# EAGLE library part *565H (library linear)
PLL

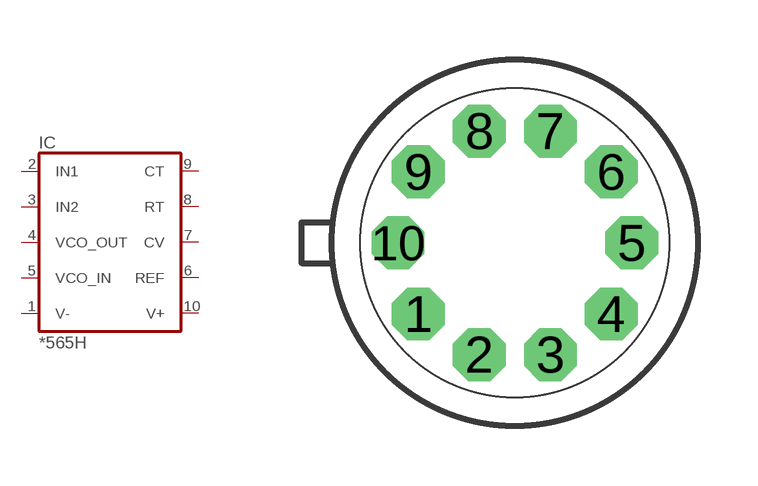
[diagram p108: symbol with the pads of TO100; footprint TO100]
Designator prefix IC

## LM565H  [TO100]
1  V-  pwr
2  IN1  in
3  IN2  in
4  VCO_OUT  out
5  VCO_IN  in
6  REF  out
7  CV  in
8  RT  pas
9  CT  pas
10  V+  pwr

## Footprint TO100 (pad centres in mm)
Metal Can Package
drill 0.813 octagon: 1 -2.413,-1.778; 2 -0.889,-2.794; 3 0.889,-2.794; 4 2.413,-1.778; 5 2.921,0; 6 2.413,1.778; 7 0.889,2.794; 8 -0.889,2.794; 9 -2.413,1.778; 10 -2.921,0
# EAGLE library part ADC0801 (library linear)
8-bit A/D CONVERTER

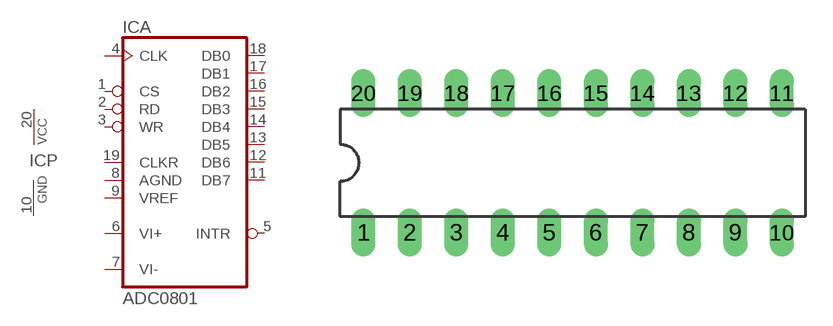
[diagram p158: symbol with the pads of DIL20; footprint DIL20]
Designator prefix IC; gates A=ADC0801 P=PWRN

## ADC0801  [DIL20]
1  A:CS  in
2  A:RD  in
3  A:WR  in
4  A:CLK  in
5  A:INTR  out
6  A:VI+  in
7  A:VI-  in
8  A:AGND  in
9  A:VREF  in
10  P:GND  pwr
11  A:DB7  out
12  A:DB6  out
13  A:DB5  out
14  A:DB4  out
15  A:DB3  out
16  A:DB2  out
17  A:DB1  out
18  A:DB0  out
19  A:CLKR  in
20  P:VCC  pwr

## Footprint DIL20 (pad centres in mm)
Dual In Line Package
drill 0.813 long: 1 -11.43,-3.81; 2 -8.89,-3.81; 3 -6.35,-3.81; 4 -3.81,-3.81; 5 -1.27,-3.81; 6 1.27,-3.81; 7 3.81,-3.81; 8 6.35,-3.81; 9 8.89,-3.81; 10 11.43,-3.81; 11 11.43,3.81; 12 8.89,3.81; 13 6.35,3.81; 14 3.81,3.81; 15 1.27,3.81; 16 -1.27,3.81; 17 -3.81,3.81; 18 -6.35,3.81; 19 -8.89,3.81; 20 -11.43,3.81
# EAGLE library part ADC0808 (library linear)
8-bit A/D CONVERTER with 8-channel multiplexer

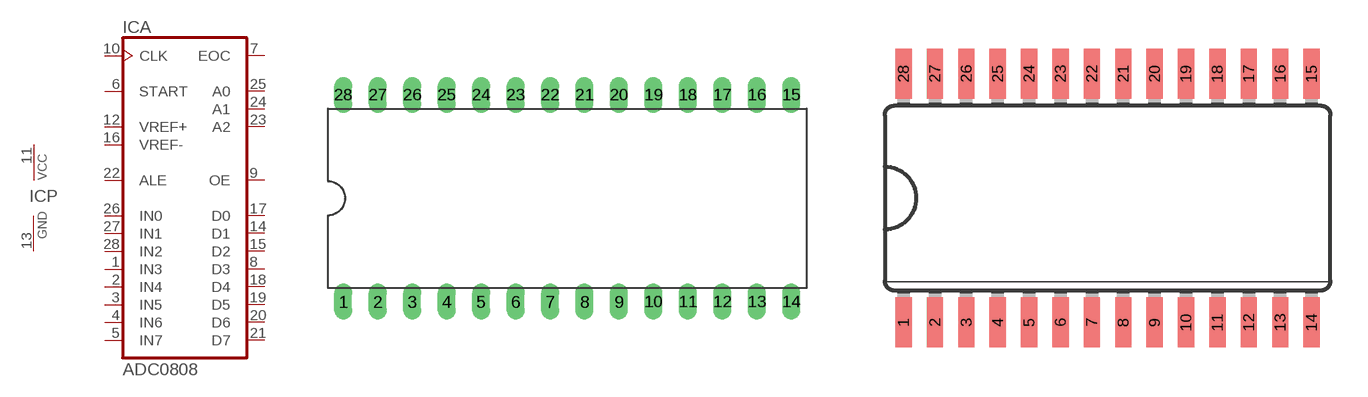
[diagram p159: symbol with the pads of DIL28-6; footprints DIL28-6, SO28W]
Designator prefix IC; gates A=ADC0808 P=PWRN

## ADC0808N  [DIL28-6]
1  A:IN3  in
2  A:IN4  in
3  A:IN5  in
4  A:IN6  in
5  A:IN7  in
6  A:START  in
7  A:EOC  out
8  A:D3  hiz
9  A:OE  in
10  A:CLK  in
11  P:VCC  pwr
12  A:VREF+  in
13  P:GND  pwr
14  A:D1  hiz
15  A:D2  hiz
16  A:VREF-  in
17  A:D0  hiz
18  A:D4  hiz
19  A:D5  hiz
20  A:D6  hiz
21  A:D7  hiz
22  A:ALE  in
23  A:A2  in
24  A:A1  in
25  A:A0  in
26  A:IN0  in
27  A:IN1  in
28  A:IN2  in

## ADC0808D  [SO28W]
Pads as for DIL28-6

## Footprint DIL28-6 (pad centres in mm)
Dual In Line Package 0.6 inch
drill 0.813 long: 1 -16.51,-7.62; 2 -13.97,-7.62; 3 -11.43,-7.62; 4 -8.89,-7.62; 5 -6.35,-7.62; 6 -3.81,-7.62; 7 -1.27,-7.62; 8 1.27,-7.62; 9 3.81,-7.62; 10 6.35,-7.62; 11 8.89,-7.62; 12 11.43,-7.62; 13 13.97,-7.62; 14 16.51,-7.62; 15 16.51,7.62; 16 13.97,7.62; 17 11.43,7.62; 18 8.89,7.62; 19 6.35,7.62; 20 3.81,7.62; 21 1.27,7.62; 22 -1.27,7.62; 23 -3.81,7.62; 24 -6.35,7.62; 25 -8.89,7.62; 26 -11.43,7.62; 27 -13.97,7.62; 28 -16.51,7.62

## Footprint SO28W (pad centres in mm)
Small Outline Package 28 wide
smd 0.66 x 2.032: 1 -8.255,-5.029; 2 -6.985,-5.029; 3 -5.715,-5.029; 4 -4.445,-5.029; 5 -3.175,-5.029; 6 -1.905,-5.029; 7 -0.635,-5.029; 8 0.635,-5.029; 9 1.905,-5.029; 10 3.175,-5.029; 11 4.445,-5.029; 12 5.715,-5.029; 13 6.985,-5.029; 14 8.255,-5.029; 15 8.255,5.029; 16 6.985,5.029; 17 5.715,5.029; 18 4.445,5.029; 19 3.175,5.029; 20 1.905,5.029; 21 0.635,5.029; 22 -0.635,5.029; 23 -1.905,5.029; 24 -3.175,5.029; 25 -4.445,5.029; 26 -5.715,5.029; 27 -6.985,5.029; 28 -8.255,5.029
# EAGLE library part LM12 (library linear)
Power OP AMP

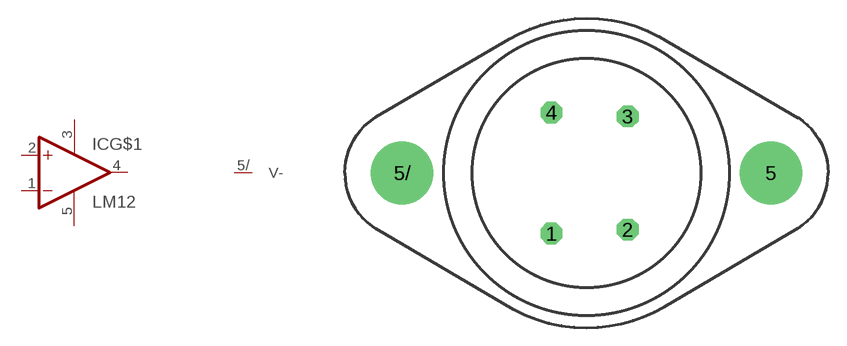
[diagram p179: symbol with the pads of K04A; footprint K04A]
Designator prefix IC; gates G$1=OPAMP+- V-2=V-

## LM12  [K04A]
1  G$1:-IN  in
2  G$1:+IN  in
3  G$1:V+  pwr
4  G$1:OUT  out
5  G$1:V-  pwr
5/  V-2:V-  pwr

## Footprint K04A (pad centres in mm)
TO-3 National Semiconductor K04A
drill 1.194 octagon: 1 -2.875,-4.972; 2 3.373,-4.648; 3 3.373,4.648; 4 -2.875,4.972
drill 4.115 round: 5 15.113,0; 5/ -15.113,0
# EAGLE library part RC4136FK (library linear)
OP AMP

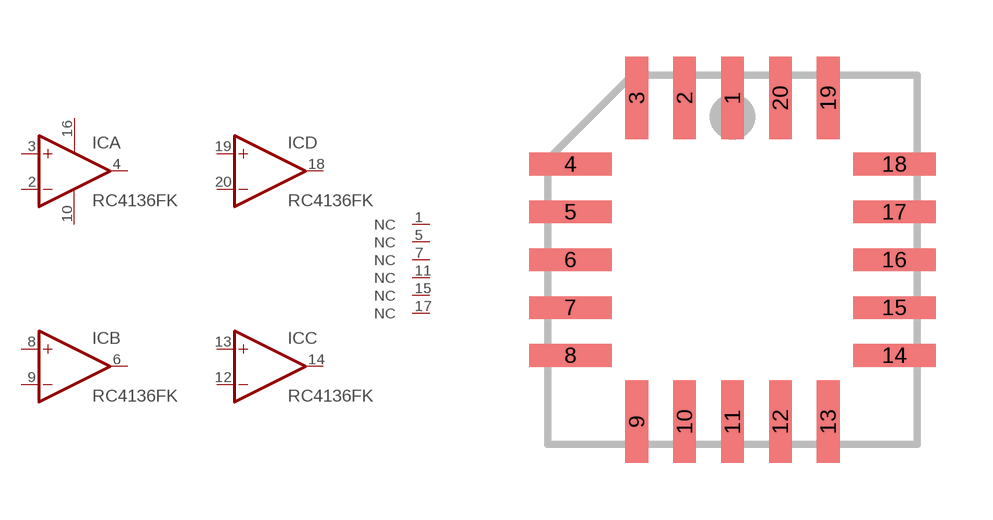
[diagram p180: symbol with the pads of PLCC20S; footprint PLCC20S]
Designator prefix IC; gates A=OPAMP B=OPAMP C=OPAMP D=OPAMP E=PWR+- 1=NC_PIN 5=NC_PIN 7=NC_PIN 11=NC_PIN 15=NC_PIN 17=NC_PIN

## RC4136FK  [PLCC20S]
1  1:NC  pas
2  A:-IN  in
3  A:+IN  in
4  A:OUT  out
5  5:NC  pas
6  B:OUT  out
7  7:NC  pas
8  B:+IN  in
9  B:-IN  in
10  E:V-  pwr
11  11:NC  pas
12  C:-IN  in
13  C:+IN  in
14  C:OUT  out
15  15:NC  pas
16  E:V+  pwr
17  17:NC  pas
18  D:OUT  out
19  D:+IN  in
20  D:-IN  in

## Footprint PLCC20S (pad centres in mm)
PLCC 20 lead square
smd 0.6 x 2.2: 1 0,4.3; 2 -1.27,4.3; 3 -2.54,4.3; 9 -2.54,-4.3; 10 -1.27,-4.3; 11 0,-4.3; 12 1.27,-4.3; 13 2.54,-4.3; 19 2.54,4.3; 20 1.27,4.3
smd 2.2 x 0.6: 4 -4.3,2.54; 5 -4.3,1.27; 6 -4.3,0; 7 -4.3,-1.27; 8 -4.3,-2.54; 14 4.3,-2.54; 15 4.3,-1.27; 16 4.3,0; 17 4.3,1.27; 18 4.3,2.54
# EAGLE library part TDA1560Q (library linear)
40 W car radio high power amplifier

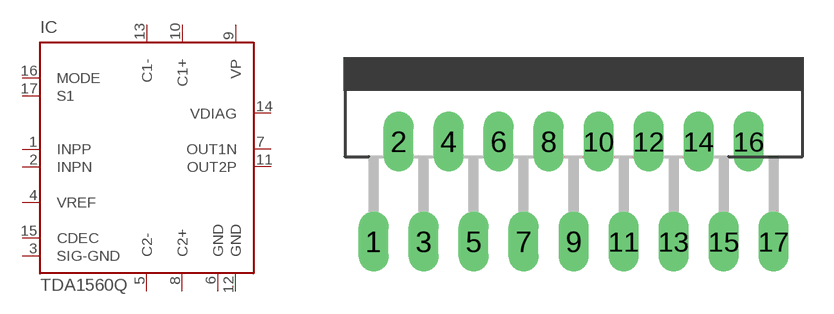
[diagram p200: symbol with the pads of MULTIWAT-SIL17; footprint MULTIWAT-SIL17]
Designator prefix IC

## TDA1560Q  [MULTIWAT-SIL17]
1  INPP  in
2  INPN  in
3  SIG-GND  in
4  VREF  pas
5  C2-  pas
6  GND  pwr
7  OUT1N  out
8  C2+  pas
9  VP  pwr
10  C1+  pas
11  OUT2P  out
12  GND  pwr
13  C1-  pas
14  VDIAG  out
15  CDEC  pas
16  MODE  in
17  S1  in

## Footprint MULTIWAT-SIL17 (pad centres in mm)
DBS17P plastic DIL-bent-SIL power package 17 leads (lead length 12 mm) SOT243-1
drill 1.016 long: 1 -10.16,-7.62; 2 -8.89,-2.54; 3 -7.62,-7.62; 4 -6.35,-2.54; 5 -5.08,-7.62; 6 -3.81,-2.54; 7 -2.54,-7.62; 8 -1.27,-2.54; 9 0,-7.62; 10 1.27,-2.54; 11 2.54,-7.62; 12 3.81,-2.54; 13 5.08,-7.62; 14 6.35,-2.54; 15 7.62,-7.62; 16 8.89,-2.54; 17 10.16,-7.62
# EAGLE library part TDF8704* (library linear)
8-bit high-speed analog-to-digital converter ADC Source: http://www.semiconductors.philips.com/acrobat_download/datasheets/TDF8704_3.pdf

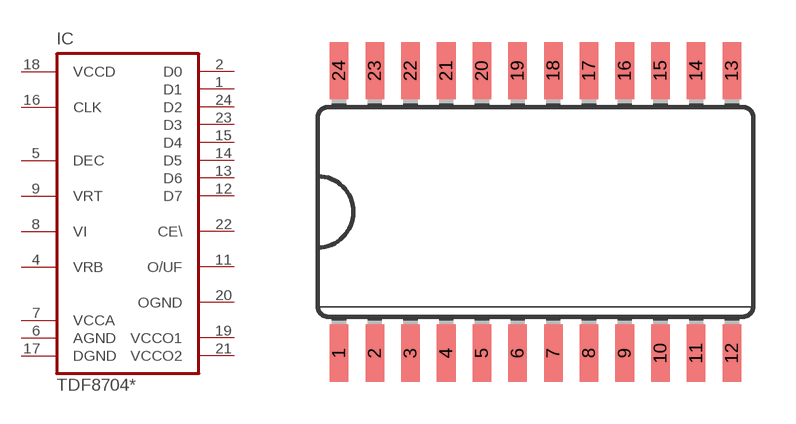
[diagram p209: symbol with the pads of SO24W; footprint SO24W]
Designator prefix IC

## TDF8704T/2, TDF8704T/4, TDF8704T/5  [SO24W]
1  D1  out
2  D0  out
4  VRB  in
5  DEC  in
6  AGND  in
7  VCCA  in
8  VI  in
9  VRT  in
11  O/UF  out
12  D7  out
13  D6  out
14  D5  out
15  D4  out
16  CLK  in
17  DGND  in
18  VCCD  in
19  VCCO1  in
20  OGND  in
21  VCCO2  in
22  CE\  in
23  D3  out
24  D2  out

## Footprint SO24W (pad centres in mm)
Small Outline Package 24 wide
smd 0.66 x 2.032: 1 -6.985,-5.029; 2 -5.715,-5.029; 3 -4.445,-5.029; 4 -3.175,-5.029; 5 -1.905,-5.029; 6 -0.635,-5.029; 7 0.635,-5.029; 8 1.905,-5.029; 9 3.175,-5.029; 10 4.445,-5.029; 11 5.715,-5.029; 12 6.985,-5.029; 13 6.985,5.029; 14 5.715,5.029; 15 4.445,5.029; 16 3.175,5.029; 17 1.905,5.029; 18 0.635,5.029; 19 -0.635,5.029; 20 -1.905,5.029; 21 -3.175,5.029; 22 -4.445,5.029; 23 -5.715,5.029; 24 -6.985,5.029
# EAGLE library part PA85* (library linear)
HIGH VOLTAGE POWER OPERATIONAL AMPLIFIER Source: http://eportal.apexmicrotech.com .. mXvtzxx.pdf

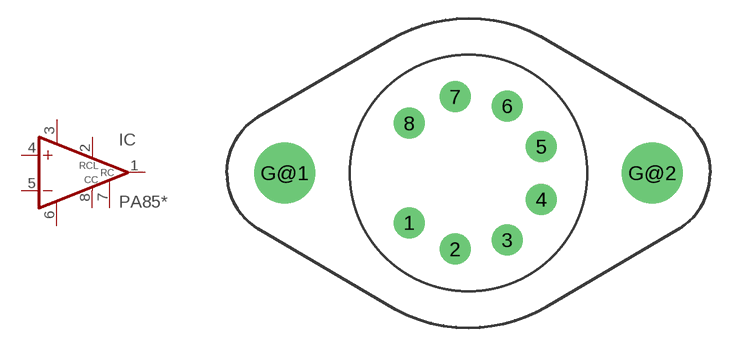
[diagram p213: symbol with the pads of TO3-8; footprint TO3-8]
Designator prefix IC

## PA85, PA85A  [TO3-8]
1  OUT  out
2  RCL  in
3  V+  pwr
4  +IN  in
5  -IN  in
6  V-  pwr
7  RC  in
8  CC  in

## Footprint TO3-8 (pad centres in mm)
8-PIN TO-3 Source: http://eportal.apexmicrotech.com/mainsite/pdf/CE.pdf
drill 1.2 pad 2.54 round: 1 -4.86,-4.08; 2 -1.1,-6.25; 3 3.18,-5.5; 4 5.97,-2.17; 5 5.97,2.17; 6 3.18,5.5; 7 -1.1,6.25; 8 -4.86,4.08
drill 4 pad 4.5 round: G@1 -15.07,0; G@2 15.07,0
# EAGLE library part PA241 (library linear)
High Voltage Power Operational Amplifier Source: eportal.apexmicrotech.com/mainsite/pdf/PA241u.pdf

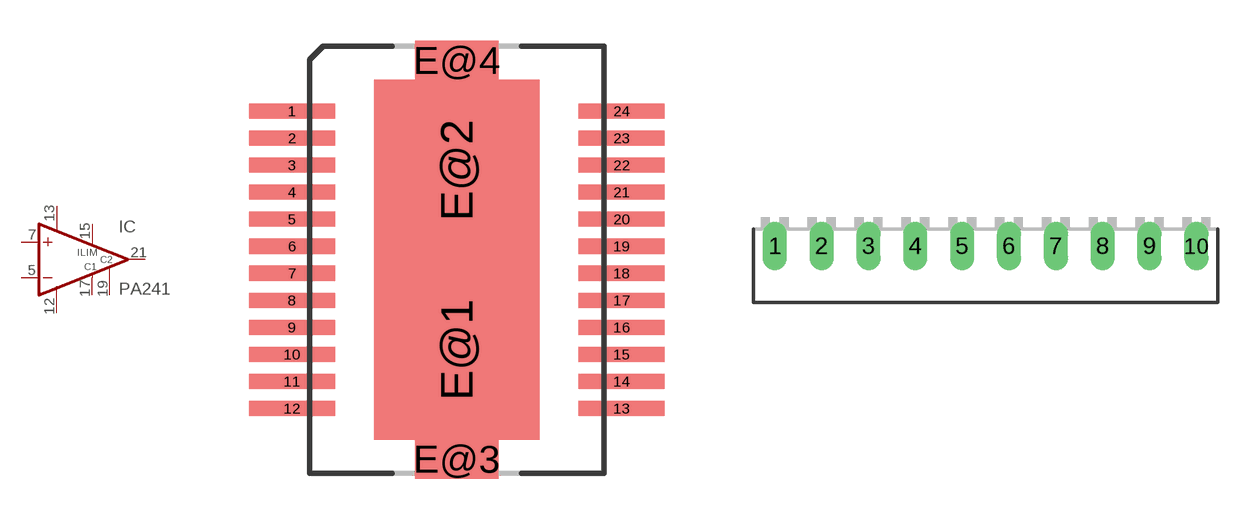
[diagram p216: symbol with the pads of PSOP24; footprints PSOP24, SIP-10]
Designator prefix IC

## PA241DF  [PSOP24]
5  -IN  in
7  +IN  in
12  V-  pwr
13  V+  pwr
15  ILIM  pas
17  C1  pas
19  C2  pas
21  OUT  out

## PA241DW  [SIP-10]
1  -IN  in
2  +IN  in
5  V-  pwr
6  V+  pwr
7  ILIM  pas
8  C2  pas
9  C1  pas
10  OUT  out

## PA241CE  [TO3-8]
1  ILIM  pas
2  C2  pas
3  C1  pas
4  OUT  out
5  -IN  in
6  +IN  in
7  V-  pwr
8  V+  pwr

## Footprint PSOP24 (pad centres in mm)
24-PIN PSOP (JEDEC MO-166) Source: http://eportal.apexmicrotech.com/mainsite/pdf/DF.pdf
smd 3.18 x 0.56: 1 -6.095,5.5; 2 -6.095,4.5; 3 -6.095,3.5; 4 -6.095,2.5; 5 -6.095,1.5; 6 -6.095,0.5; 7 -6.095,-0.5; 8 -6.095,-1.5; 9 -6.095,-2.5; 10 -6.095,-3.5; 11 -6.095,-4.5; 12 -6.095,-5.5; 13 6.095,-5.5; 14 6.095,-4.5; 15 6.095,-3.5; 16 6.095,-2.5; 17 6.095,-1.5; 18 6.095,-0.5; 19 6.095,0.5; 20 6.095,1.5; 21 6.095,2.5; 22 6.095,3.5; 23 6.095,4.5; 24 6.095,5.5
smd 6.13 x 6.67: E@1 0,-3.32; E@2 0,3.32
smd 3.07 x 1.47: E@3 0,-7.375; E@4 0,7.375

## Footprint SIP-10 (pad centres in mm)
10-Pin Ceramic SIP Source: http://eportal.apexmicrotech.com/mainsite/pdf/DW.pdf
drill 0.8 pad 1.27 long: 1 -11.43,0; 2 -8.89,0; 3 -6.35,0; 4 -3.81,0; 5 -1.27,0; 6 1.27,0; 7 3.81,0; 8 6.35,0; 9 8.89,0; 10 11.43,0

## Footprint TO3-8 (pad centres in mm)
8-PIN TO-3 Source: http://eportal.apexmicrotech.com/mainsite/pdf/CE.pdf
drill 1.2 pad 2.54 round: 1 -4.86,-4.08; 2 -1.1,-6.25; 3 3.18,-5.5; 4 5.97,-2.17; 5 5.97,2.17; 6 3.18,5.5; 7 -1.1,6.25; 8 -4.86,4.08
drill 4 pad 4.5 round: G@1 -15.07,0; G@2 15.07,0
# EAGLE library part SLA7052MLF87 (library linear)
UNIPOLAR STEPPER-MOTOR TRANSLATOR/PWM DRIVER Source: http://www.allegromicro.com/datafile/97052.pdf

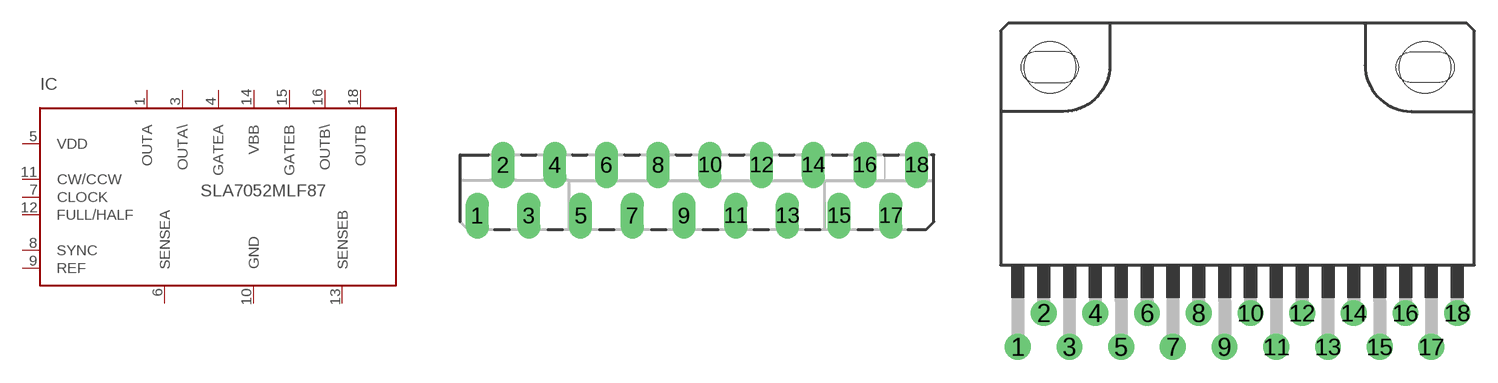
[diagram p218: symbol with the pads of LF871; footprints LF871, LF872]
Designator prefix IC

## SLA7052MLF871  [LF871]
1  OUTA  out
3  OUTA\  out
4  GATEA  in
5  VDD  pwr
6  SENSEA  in
7  CLOCK  in
8  SYNC  in
9  REF  in
10  GND  pwr
11  CW/CCW  in
12  FULL/HALF  in
13  SENSEB  in
14  VBB  pwr
15  GATEB  in
16  OUTB\  out
18  OUTB  out

## SLA7052MLF872  [LF872]
Pads as for LF871

## Footprint LF871 (pad centres in mm)
18-pin single in-line power-tab package LF871 Source: //www.allegromicro.com/datafile/97052.pdf
drill 1 pad 1.422 long: 1 -14.28,-1.65; 2 -12.6,1.65; 3 -10.92,-1.65; 4 -9.24,1.65; 5 -7.56,-1.65; 6 -5.88,1.65; 7 -4.2,-1.65; 8 -2.52,1.65; 9 -0.84,-1.65; 10 0.84,1.65; 11 2.52,-1.65; 12 4.2,1.65; 13 5.88,-1.65; 14 7.56,1.65; 15 9.24,-1.65; 16 10.92,1.65; 17 12.6,-1.65; 18 14.28,1.65

## Footprint LF872 (pad centres in mm)
18-pin single in-line power-tab package LF872 Source: http://www.allegromicro.com/datafile/97052.pdf
drill 1 pad 1.676 round: 1 -14.28,-2.2; 2 -12.6,0; 3 -10.92,-2.2; 4 -9.24,0; 5 -7.56,-2.2; 6 -5.88,0; 7 -4.2,-2.2; 8 -2.52,0; 9 -0.84,-2.2; 10 0.84,0; 11 2.52,-2.2; 12 4.2,0; 13 5.88,-2.2; 14 7.56,0; 15 9.24,-2.2; 16 10.92,0; 17 12.6,-2.2; 18 14.28,0
hole 3.35 at -12.2,16
hole 3.35 at 12.2,16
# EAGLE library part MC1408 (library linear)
8-bit Multiplying D/A Converter Source: http://www.onsemi.com/pub/Collateral/MC1408 DATASHEET.PDF

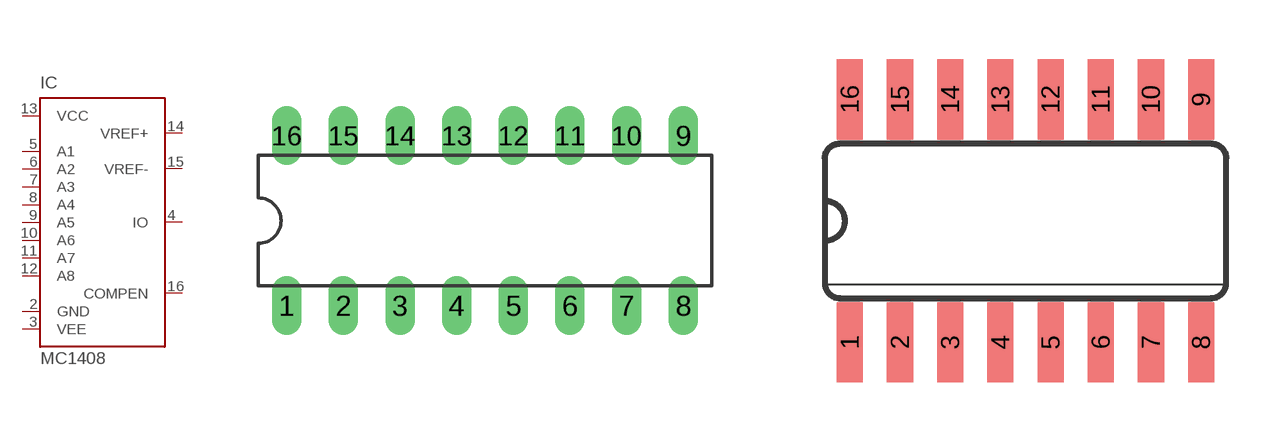
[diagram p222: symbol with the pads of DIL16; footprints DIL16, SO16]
Designator prefix IC

## MC1408N  [DIL16]
2  GND  pwr
3  VEE  pwr
4  IO
5  A1  in
6  A2  in
7  A3  in
8  A4  in
9  A5  in
10  A6  in
11  A7  in
12  A8  in
13  VCC  pwr
14  VREF+  in
15  VREF-  in
16  COMPEN  pas

## MC1408D  [SO16]
1  VCC  pwr
2  VREF+  in
3  VREF-  in
4  COMPEN  pas
6  GND  pwr
7  VEE  pwr
8  IO
9  A1  in
10  A2  in
11  A3  in
12  A4  in
13  A5  in
14  A6  in
15  A7  in
16  A8  in

## Footprint DIL16 (pad centres in mm)
Dual In Line Package
drill 0.813 long: 1 -8.89,-3.81; 2 -6.35,-3.81; 3 -3.81,-3.81; 4 -1.27,-3.81; 5 1.27,-3.81; 6 3.81,-3.81; 7 6.35,-3.81; 8 8.89,-3.81; 9 8.89,3.81; 10 6.35,3.81; 11 3.81,3.81; 12 1.27,3.81; 13 -1.27,3.81; 14 -3.81,3.81; 15 -6.35,3.81; 16 -8.89,3.81

## Footprint SO16 (pad centres in mm)
Small Outline Package 16
smd 0.66 x 2.032: 1 -4.445,-3.073; 2 -3.175,-3.073; 3 -1.905,-3.073; 4 -0.635,-3.073; 5 0.635,-3.073; 6 1.905,-3.073; 7 3.175,-3.073; 8 4.445,-3.073; 9 4.445,3.073; 10 3.175,3.073; 11 1.905,3.073; 12 0.635,3.073; 13 -0.635,3.073; 14 -1.905,3.073; 15 -3.175,3.073; 16 -4.445,3.073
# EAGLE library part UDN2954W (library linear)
FULL-BRIDGE PWM MOTOR DRIVER Allegro Microsystems Source: http://allegromicro.com/datafile/archive/2953.pdf

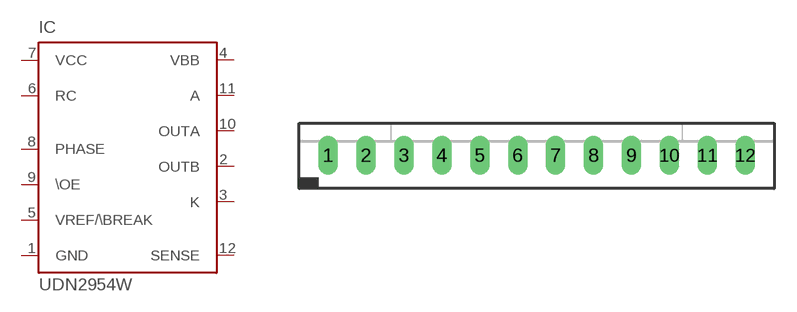
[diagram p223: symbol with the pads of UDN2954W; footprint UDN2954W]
Designator prefix IC

## UDN2954W  [UDN2954W]
1  GND  pwr
2  OUTB  out
3  K  in
4  VBB  pwr
5  VREF/\BREAK  in
6  RC  in
7  VCC  pwr
8  PHASE  in
9  \OE  in
10  OUTA  out
11  A  in
12  SENSE  in

## Footprint UDN2954W (pad centres in mm)
SIP 12 Source: http://allegromicro.com/datafile/archive/2953.pdf
drill 0.8 pad 1.27 long: 1 -13.97,0; 2 -11.43,0; 3 -8.89,0; 4 -6.35,0; 5 -3.81,0; 6 -1.27,0; 7 1.27,0; 8 3.81,0; 9 6.35,0; 10 8.89,0; 11 11.43,0; 12 13.97,0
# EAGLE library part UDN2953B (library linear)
FULL-BRIDGE PWM MOTOR DRIVER Allegro Microsystems Source: http://allegromicro.com/datafile/archive/2953.pdf

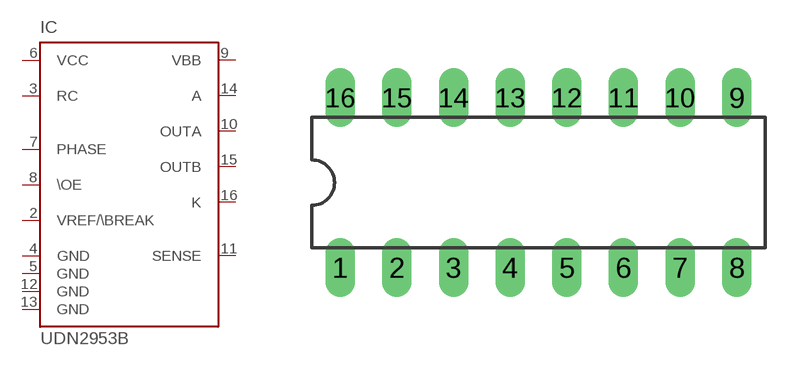
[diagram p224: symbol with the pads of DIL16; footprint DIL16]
Designator prefix IC

## UDN2953B  [DIL16]
2  VREF/\BREAK  in
3  RC  in
4  GND  pwr
5  GND  pwr
6  VCC  pwr
7  PHASE  in
8  \OE  in
9  VBB  pwr
10  OUTA  out
11  SENSE  in
12  GND  pwr
13  GND  pwr
14  A  in
15  OUTB  out
16  K  in

## Footprint DIL16 (pad centres in mm)
Dual In Line Package
drill 0.813 long: 1 -8.89,-3.81; 2 -6.35,-3.81; 3 -3.81,-3.81; 4 -1.27,-3.81; 5 1.27,-3.81; 6 3.81,-3.81; 7 6.35,-3.81; 8 8.89,-3.81; 9 8.89,3.81; 10 6.35,3.81; 11 3.81,3.81; 12 1.27,3.81; 13 -1.27,3.81; 14 -3.81,3.81; 15 -6.35,3.81; 16 -8.89,3.81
